One B-rep face of a CAD part: STEP entity #356.
In plain terms, the planar face has unit normal (0, 0, 1).
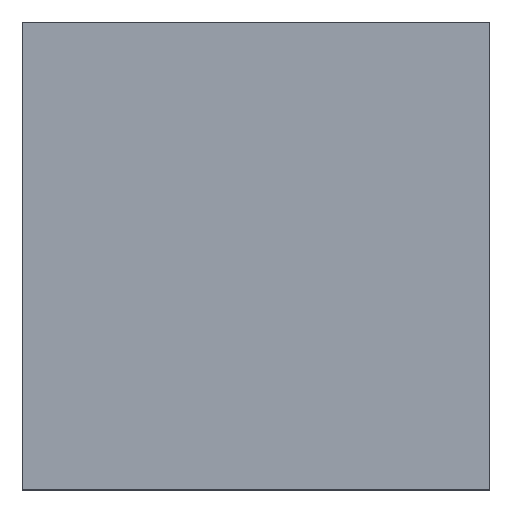
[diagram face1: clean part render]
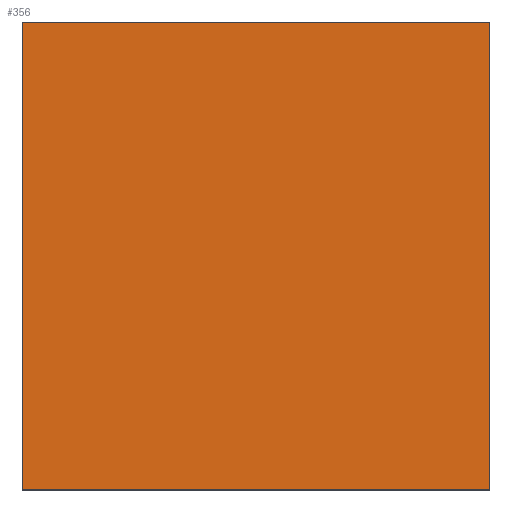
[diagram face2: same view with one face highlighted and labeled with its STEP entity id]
Its self-contained STEP definition (entity closure, numbers rounded to 3 decimals):
#42 = VERTEX_POINT('',#43);
#43 = CARTESIAN_POINT('',(-2.,-2.,1.6));
#50 = PLANE('',#51);
#51 = AXIS2_PLACEMENT_3D('',#52,#53,#54);
#52 = CARTESIAN_POINT('',(-2.,-2.,0.));
#53 = DIRECTION('',(1.,0.,0.));
#54 = DIRECTION('',(0.,0.,1.));
#62 = PLANE('',#63);
#63 = AXIS2_PLACEMENT_3D('',#64,#65,#66);
#64 = CARTESIAN_POINT('',(-2.,-2.,0.));
#65 = DIRECTION('',(0.,1.,0.));
#66 = DIRECTION('',(0.,0.,1.));
#103 = VERTEX_POINT('',#104);
#104 = CARTESIAN_POINT('',(-2.,2.,1.6));
#118 = PLANE('',#119);
#119 = AXIS2_PLACEMENT_3D('',#120,#121,#122);
#120 = CARTESIAN_POINT('',(-2.,2.,0.));
#121 = DIRECTION('',(0.,1.,0.));
#122 = DIRECTION('',(0.,0.,1.));
#130 = EDGE_CURVE('',#42,#103,#131,.T.);
#131 = SURFACE_CURVE('',#132,(#136,#143),.PCURVE_S1.);
#132 = LINE('',#133,#134);
#133 = CARTESIAN_POINT('',(-2.,-2.,1.6));
#134 = VECTOR('',#135,1.);
#135 = DIRECTION('',(0.,1.,0.));
#136 = PCURVE('',#50,#137);
#137 = DEFINITIONAL_REPRESENTATION('',(#138),#142);
#138 = LINE('',#139,#140);
#139 = CARTESIAN_POINT('',(1.6,0.));
#140 = VECTOR('',#141,1.);
#141 = DIRECTION('',(0.,-1.));
#142 = ( GEOMETRIC_REPRESENTATION_CONTEXT(2)
PARAMETRIC_REPRESENTATION_CONTEXT() REPRESENTATION_CONTEXT('2D SPACE',''
  ) );
#143 = PCURVE('',#144,#149);
#144 = PLANE('',#145);
#145 = AXIS2_PLACEMENT_3D('',#146,#147,#148);
#146 = CARTESIAN_POINT('',(-2.,-2.,1.6));
#147 = DIRECTION('',(0.,0.,1.));
#148 = DIRECTION('',(1.,0.,0.));
#149 = DEFINITIONAL_REPRESENTATION('',(#150),#154);
#150 = LINE('',#151,#152);
#151 = CARTESIAN_POINT('',(0.,0.));
#152 = VECTOR('',#153,1.);
#153 = DIRECTION('',(0.,1.));
#154 = ( GEOMETRIC_REPRESENTATION_CONTEXT(2)
PARAMETRIC_REPRESENTATION_CONTEXT() REPRESENTATION_CONTEXT('2D SPACE',''
  ) );
#162 = VERTEX_POINT('',#163);
#163 = CARTESIAN_POINT('',(2.,-2.,1.6));
#170 = PLANE('',#171);
#171 = AXIS2_PLACEMENT_3D('',#172,#173,#174);
#172 = CARTESIAN_POINT('',(2.,-2.,0.));
#173 = DIRECTION('',(1.,0.,0.));
#174 = DIRECTION('',(0.,0.,1.));
#213 = VERTEX_POINT('',#214);
#214 = CARTESIAN_POINT('',(2.,2.,1.6));
#235 = EDGE_CURVE('',#162,#213,#236,.T.);
#236 = SURFACE_CURVE('',#237,(#241,#248),.PCURVE_S1.);
#237 = LINE('',#238,#239);
#238 = CARTESIAN_POINT('',(2.,-2.,1.6));
#239 = VECTOR('',#240,1.);
#240 = DIRECTION('',(0.,1.,0.));
#241 = PCURVE('',#170,#242);
#242 = DEFINITIONAL_REPRESENTATION('',(#243),#247);
#243 = LINE('',#244,#245);
#244 = CARTESIAN_POINT('',(1.6,0.));
#245 = VECTOR('',#246,1.);
#246 = DIRECTION('',(0.,-1.));
#247 = ( GEOMETRIC_REPRESENTATION_CONTEXT(2)
PARAMETRIC_REPRESENTATION_CONTEXT() REPRESENTATION_CONTEXT('2D SPACE',''
  ) );
#248 = PCURVE('',#144,#249);
#249 = DEFINITIONAL_REPRESENTATION('',(#250),#254);
#250 = LINE('',#251,#252);
#251 = CARTESIAN_POINT('',(4.,0.));
#252 = VECTOR('',#253,1.);
#253 = DIRECTION('',(0.,1.));
#254 = ( GEOMETRIC_REPRESENTATION_CONTEXT(2)
PARAMETRIC_REPRESENTATION_CONTEXT() REPRESENTATION_CONTEXT('2D SPACE',''
  ) );
#281 = EDGE_CURVE('',#42,#162,#282,.T.);
#282 = SURFACE_CURVE('',#283,(#287,#294),.PCURVE_S1.);
#283 = LINE('',#284,#285);
#284 = CARTESIAN_POINT('',(-2.,-2.,1.6));
#285 = VECTOR('',#286,1.);
#286 = DIRECTION('',(1.,0.,0.));
#287 = PCURVE('',#62,#288);
#288 = DEFINITIONAL_REPRESENTATION('',(#289),#293);
#289 = LINE('',#290,#291);
#290 = CARTESIAN_POINT('',(1.6,0.));
#291 = VECTOR('',#292,1.);
#292 = DIRECTION('',(0.,1.));
#293 = ( GEOMETRIC_REPRESENTATION_CONTEXT(2)
PARAMETRIC_REPRESENTATION_CONTEXT() REPRESENTATION_CONTEXT('2D SPACE',''
  ) );
#294 = PCURVE('',#144,#295);
#295 = DEFINITIONAL_REPRESENTATION('',(#296),#300);
#296 = LINE('',#297,#298);
#297 = CARTESIAN_POINT('',(0.,0.));
#298 = VECTOR('',#299,1.);
#299 = DIRECTION('',(1.,0.));
#300 = ( GEOMETRIC_REPRESENTATION_CONTEXT(2)
PARAMETRIC_REPRESENTATION_CONTEXT() REPRESENTATION_CONTEXT('2D SPACE',''
  ) );
#328 = EDGE_CURVE('',#103,#213,#329,.T.);
#329 = SURFACE_CURVE('',#330,(#334,#341),.PCURVE_S1.);
#330 = LINE('',#331,#332);
#331 = CARTESIAN_POINT('',(-2.,2.,1.6));
#332 = VECTOR('',#333,1.);
#333 = DIRECTION('',(1.,0.,0.));
#334 = PCURVE('',#118,#335);
#335 = DEFINITIONAL_REPRESENTATION('',(#336),#340);
#336 = LINE('',#337,#338);
#337 = CARTESIAN_POINT('',(1.6,0.));
#338 = VECTOR('',#339,1.);
#339 = DIRECTION('',(0.,1.));
#340 = ( GEOMETRIC_REPRESENTATION_CONTEXT(2)
PARAMETRIC_REPRESENTATION_CONTEXT() REPRESENTATION_CONTEXT('2D SPACE',''
  ) );
#341 = PCURVE('',#144,#342);
#342 = DEFINITIONAL_REPRESENTATION('',(#343),#347);
#343 = LINE('',#344,#345);
#344 = CARTESIAN_POINT('',(0.,4.));
#345 = VECTOR('',#346,1.);
#346 = DIRECTION('',(1.,0.));
#347 = ( GEOMETRIC_REPRESENTATION_CONTEXT(2)
PARAMETRIC_REPRESENTATION_CONTEXT() REPRESENTATION_CONTEXT('2D SPACE',''
  ) );
#356 = ADVANCED_FACE('',(#357),#144,.T.);
#357 = FACE_BOUND('',#358,.T.);
#358 = EDGE_LOOP('',(#359,#360,#361,#362));
#359 = ORIENTED_EDGE('',*,*,#130,.F.);
#360 = ORIENTED_EDGE('',*,*,#281,.T.);
#361 = ORIENTED_EDGE('',*,*,#235,.T.);
#362 = ORIENTED_EDGE('',*,*,#328,.F.);
